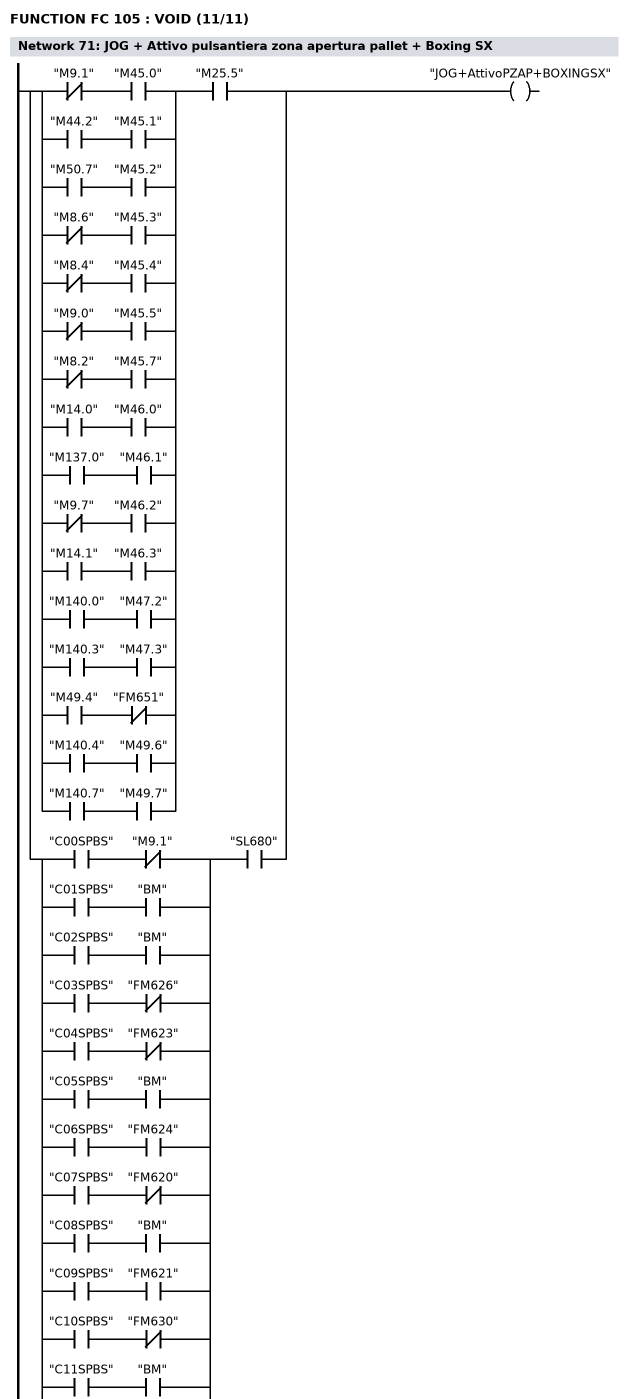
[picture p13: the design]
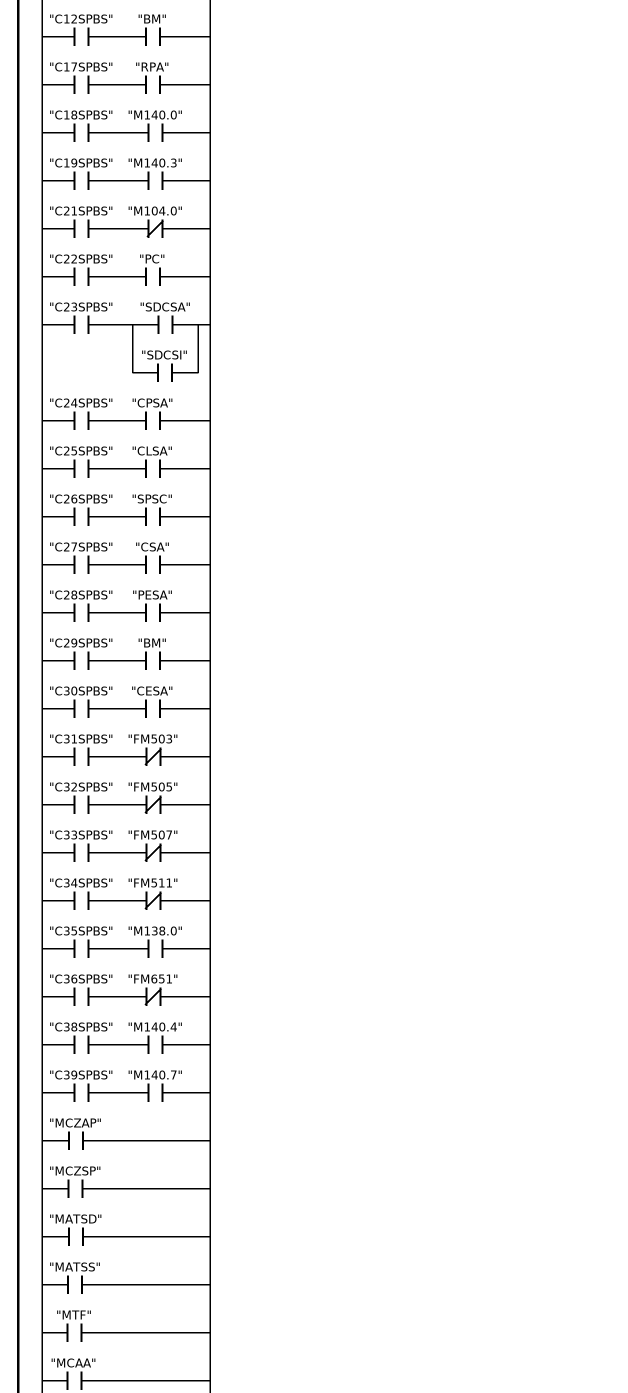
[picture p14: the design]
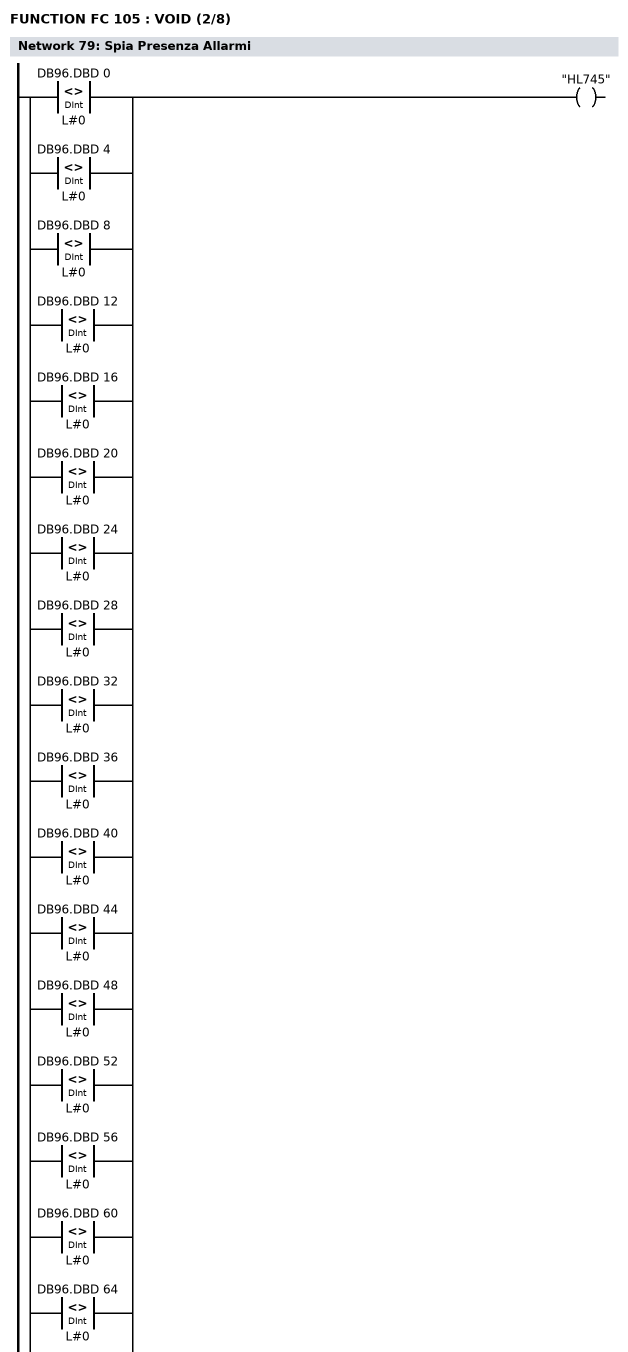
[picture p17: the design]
FUNCTION FC 105 : VOID
TITLE =Gestione Output
AUTHOR : MassimoZ
FAMILY : NovaSrl
VERSION : 0.1

BEGIN
NETWORK
TITLE =Avanti Apertura Pallet

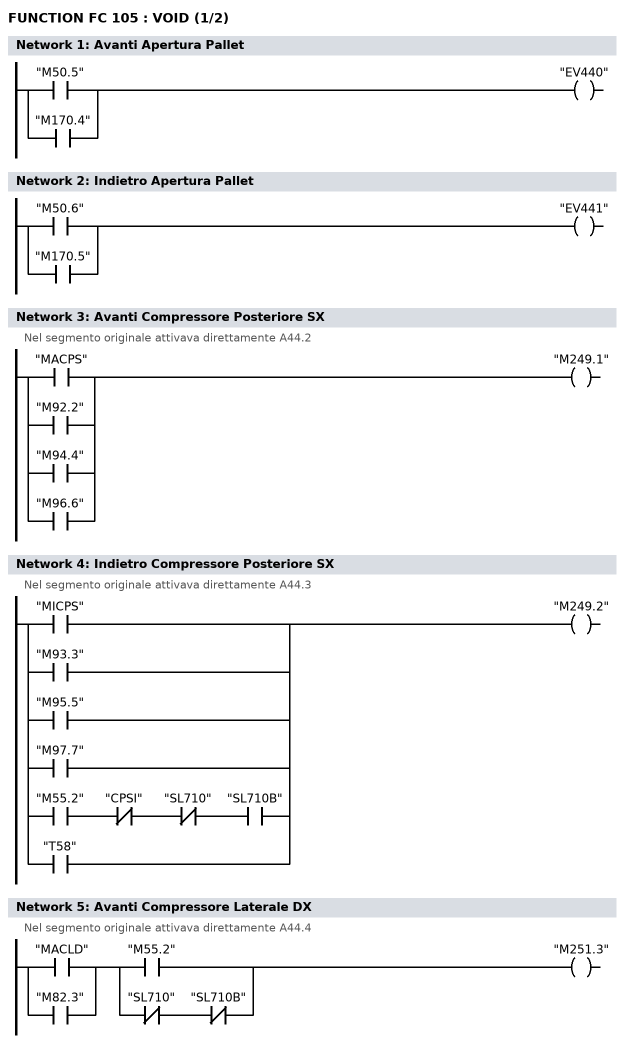
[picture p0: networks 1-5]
      O     "M50.5";
      O     "M170.4";
      =     "EV440";
NETWORK
TITLE =Indietro Apertura Pallet

      O     "M50.6";
      O     "M170.5";
      =     "EV441";
NETWORK
TITLE =Avanti Compressore Posteriore SX
//Nel segmento originale attivava direttamente A44.2
      O     "MACPS";
      O     "M92.2";
      O     "M94.4";
      O     "M96.6";
      =     "M249.1";
NETWORK
TITLE =Indietro Compressore Posteriore SX
//Nel segmento originale attivava direttamente A44.3
      O     "MICPS";
      O     "M93.3";
      O     "M95.5";
      O     "M97.7";
      O     ;
      U     "M55.2";
      UN    "CPSI";
      UN    "SL710";
      U     "SL710B";
      O     "T58";
      =     "M249.2";
NETWORK
TITLE =Avanti Compressore Laterale DX
//Nel segmento originale attivava direttamente A44.4
      U(    ;
      O     "MACLD";
      O     "M82.3";
      )     ;
      U(    ;
      O     "M55.2";
      O     ;
      UN    "SL710";
      UN    "SL710B";
      )     ;
      =     "M251.3";
NETWORK
TITLE =Indietro Compressore Laterale DX
//Nel segmento originale attivava direttamente A44.5
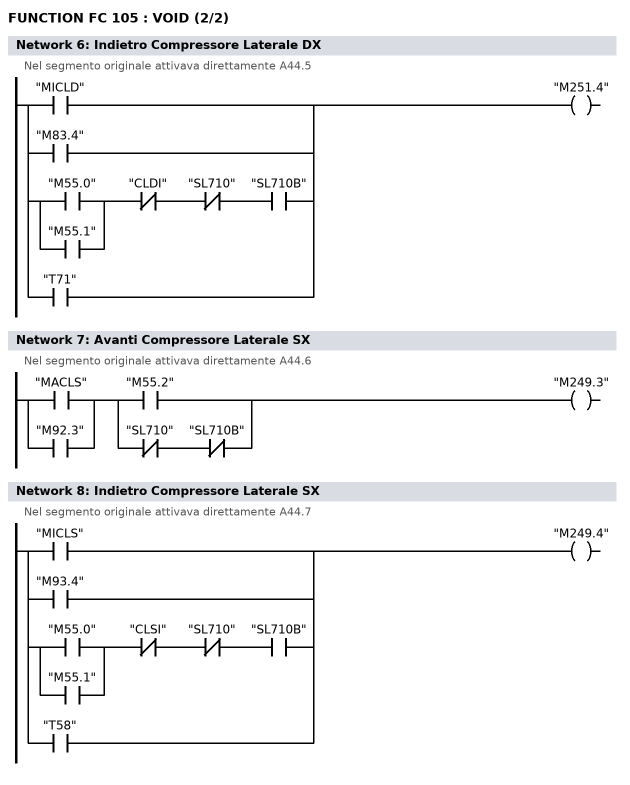
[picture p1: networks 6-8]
      O     "MICLD";
      O     "M83.4";
      O     ;
      U(    ;
      O     "M55.0";
      O     "M55.1";
      )     ;
      UN    "CLDI";
      UN    "SL710";
      U     "SL710B";
      O     "T71";
      =     "M251.4";
NETWORK
TITLE =Avanti Compressore Laterale SX
//Nel segmento originale attivava direttamente A44.6
      U(    ;
      O     "MACLS";
      O     "M92.3";
      )     ;
      U(    ;
      O     "M55.2";
      O     ;
      UN    "SL710";
      UN    "SL710B";
      )     ;
      =     "M249.3";
NETWORK
TITLE =Indietro Compressore Laterale SX
//Nel segmento originale attivava direttamente A44.7
      O     "MICLS";
      O     "M93.4";
      O     ;
      U(    ;
      O     "M55.0";
      O     "M55.1";
      )     ;
      UN    "CLSI";
      UN    "SL710";
      U     "SL710B";
      O     "T58";
      =     "M249.4";
NETWORK
TITLE =Abilita modifica per 12FLB540-CASSA DI COMPRESSIONE SX

      U     "E73.3";
      =     "M249.0";
// Gestione tradizionale con compressore laterale per 1 piantaggio
// e posteriore per 2 e 3 piantaggi
      UN    "M249.0";
      SPBN  M00b;
      U     "M249.1";
      =     "EV442";
      U     "M249.2";
      =     "EV443";
      U     "M249.3";
      =     "EV446";
      U     "M249.4";
      =     "EV447";
M00b: NOP   0;
// Gestione per 12FLB540 con compressore posteriore per 1 piantaggio
// e laterale per 2 e 3 piantaggi
      U     "M249.0";
      SPBN  M00c;
      U     "M249.1";
      =     "EV446";
      U     "M249.2";
      =     "EV447";
      U     "M249.3";
      =     "EV442";
      U     "M249.4";
      =     "EV443";
M00c: NOP   0;

NETWORK
TITLE =Avanti Compressore Posteriore DX
//Nel segmento originale attivava direttamente A45.0
//
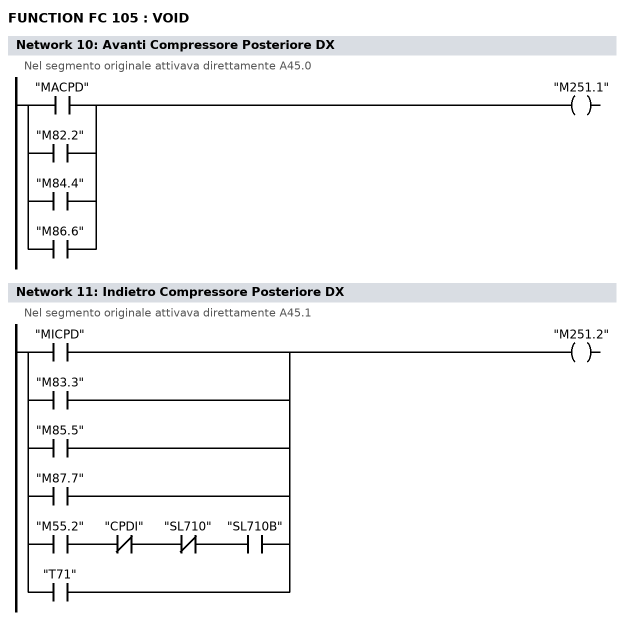
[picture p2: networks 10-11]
      O     "MACPD";
      O     "M82.2";
      O     "M84.4";
      O     "M86.6";
      =     "M251.1";
NETWORK
TITLE =Indietro Compressore Posteriore DX
//Nel segmento originale attivava direttamente A45.1
      O     "MICPD";
      O     "M83.3";
      O     "M85.5";
      O     "M87.7";
      O     ;
      U     "M55.2";
      UN    "CPDI";
      UN    "SL710";
      U     "SL710B";
      O     "T71";
      =     "M251.2";
NETWORK
TITLE =Abilita modifica per 12FLB540-CASSA DI COMPRESSIONE DX

      U     "E73.3";
      =     "M251.0";
// Gestione tradizionale con compressore laterale per 1 piantaggio
// e posteriore per 2 e 3 piantaggi
      UN    "M251.0";
      SPBN  D00b;
      U     "M251.1";
      =     "EV450";
      U     "M251.2";
      =     "EV451";
      U     "M251.3";
      =     "EV444";
      U     "M251.4";
      =     "EV445";
D00b: NOP   0;
// Gestione per 12FLB540 con compressore posteriore per 1 piantaggio
// e laterale per 2 e 3 piantaggi
      U     "M251.0";
      SPBN  D00c;
      U     "M251.1";
      =     "EV444";
      U     "M251.2";
      =     "EV445";
      U     "M251.3";
      =     "EV450";
      U     "M251.4";
      =     "EV451";
D00c: NOP   0;

NETWORK
TITLE =Salita Piantaggio Elementi SX

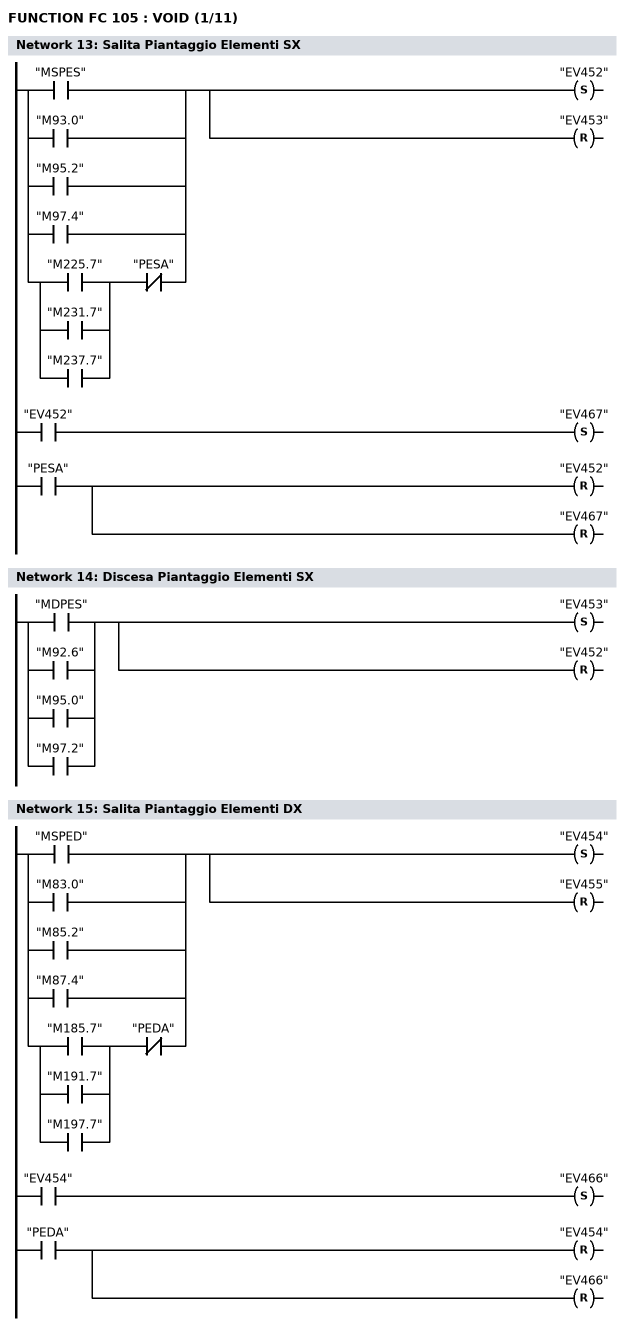
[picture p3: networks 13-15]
      O     "MSPES";
      O     "M93.0";
      O     "M95.2";
      O     "M97.4";
      O(    ;
      O     "M225.7";
      O     "M231.7";
      O     "M237.7";
      UN    "PESA";
      )     ;
      S     "EV452";
      R     "EV453";

      U     "EV452";
      S     "EV467";

      U     "PESA";
      R     "EV452";
      R     "EV467";
NETWORK
TITLE =Discesa Piantaggio Elementi SX

      O     "MDPES";
      O     "M92.6";
      O     "M95.0";
      O     "M97.2";
      S     "EV453";
      R     "EV452";
NETWORK
TITLE =Salita Piantaggio Elementi DX

      O     "MSPED";
      O     "M83.0";
      O     "M85.2";
      O     "M87.4";
      O(    ;
      O     "M185.7";
      O     "M191.7";
      O     "M197.7";
      UN    "PEDA";
      )     ;
      S     "EV454";
      R     "EV455";

      U     "EV454";
      S     "EV466";

      U     "PEDA";
      R     "EV454";
      R     "EV466";
NETWORK
TITLE =Discesa Piantaggio Elementi DX

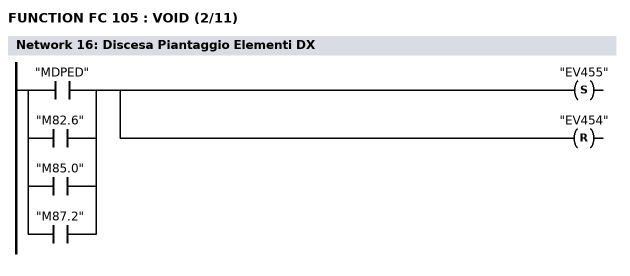
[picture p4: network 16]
      O     "MDPED";
      O     "M82.6";
      O     "M85.0";
      O     "M87.2";
      S     "EV455";
      R     "EV454";
NETWORK
TITLE =EV Pilota Centralina Idraulica

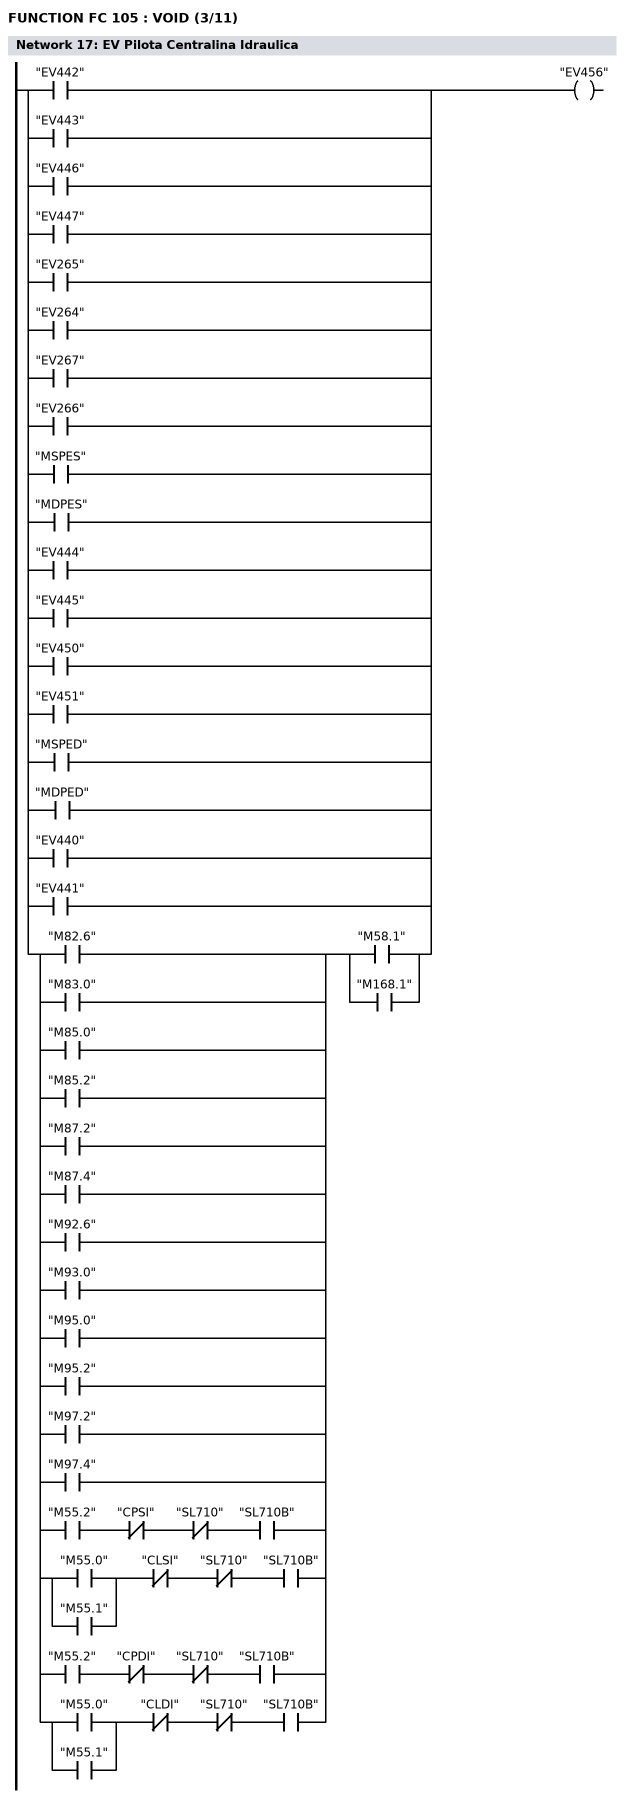
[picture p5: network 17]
      O     "EV442";
      O     "EV443";
      O     "EV446";
      O     "EV447";
      O     "EV265";
      O     "EV264";
      O     "EV267";
      O     "EV266";
      O     "MSPES";
      O     "MDPES";
      O     "EV444";
      O     "EV445";
      O     "EV450";
      O     "EV451";
      O     "MSPED";
      O     "MDPED";
      O     "EV440";
      O     "EV441";
      O     ;
      U(    ;
      O     "M82.6";
      O     "M83.0";
      O     "M85.0";
      O     "M85.2";
      O     "M87.2";
      O     "M87.4";
      O     "M92.6";
      O     "M93.0";
      O     "M95.0";
      O     "M95.2";
      O     "M97.2";
      O     "M97.4";
      O     ;
      U     "M55.2";
      UN    "CPSI";
      UN    "SL710";
      U     "SL710B";
      O     ;
      U(    ;
      O     "M55.0";
      O     "M55.1";
      )     ;
      UN    "CLSI";
      UN    "SL710";
      U     "SL710B";
      O     ;
      U     "M55.2";
      UN    "CPDI";
      UN    "SL710";
      U     "SL710B";
      O     ;
      U(    ;
      O     "M55.0";
      O     "M55.1";
      )     ;
      UN    "CLDI";
      UN    "SL710";
      U     "SL710B";
      )     ;
      U(    ;
      O     "M58.1";
      O     "M168.1";
      )     ;
      =     "EV456";
NETWORK
TITLE =Avanti cadenziatore Entrata SX

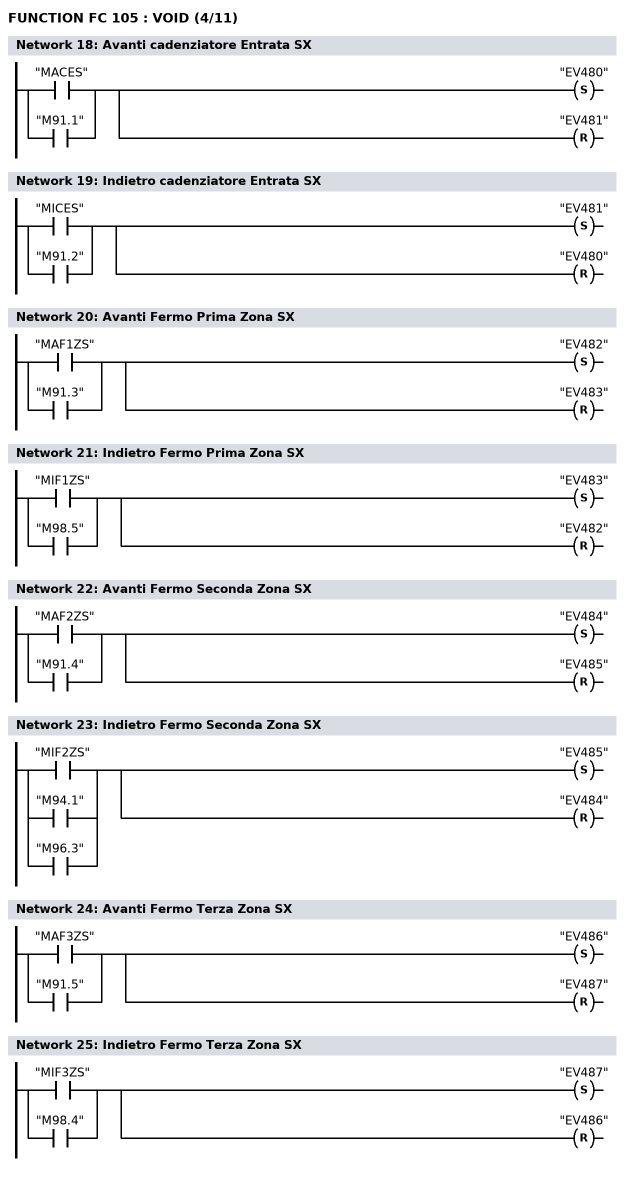
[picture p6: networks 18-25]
      O     "MACES";
      O     "M91.1";
      S     "EV480";
      R     "EV481";
NETWORK
TITLE =Indietro cadenziatore Entrata SX

      O     "MICES";
      O     "M91.2";
      S     "EV481";
      R     "EV480";
NETWORK
TITLE =Avanti Fermo Prima Zona SX

      O     "MAF1ZS";
      O     "M91.3";
      S     "EV482";
      R     "EV483";
NETWORK
TITLE =Indietro Fermo Prima Zona SX

      O     "MIF1ZS";
      O     "M98.5";
      S     "EV483";
      R     "EV482";
NETWORK
TITLE =Avanti Fermo Seconda Zona SX

      O     "MAF2ZS";
      O     "M91.4";
      S     "EV484";
      R     "EV485";
NETWORK
TITLE =Indietro Fermo Seconda Zona SX

      O     "MIF2ZS";
      O     "M94.1";
      O     "M96.3";
      S     "EV485";
      R     "EV484";
NETWORK
TITLE =Avanti Fermo Terza Zona SX

      O     "MAF3ZS";
      O     "M91.5";
      S     "EV486";
      R     "EV487";
NETWORK
TITLE =Indietro Fermo Terza Zona SX

      O     "MIF3ZS";
      O     "M98.4";
      S     "EV487";
      R     "EV486";
NETWORK
TITLE =Avanti Bloccaggio pezzo in Zona di Lavoro SX

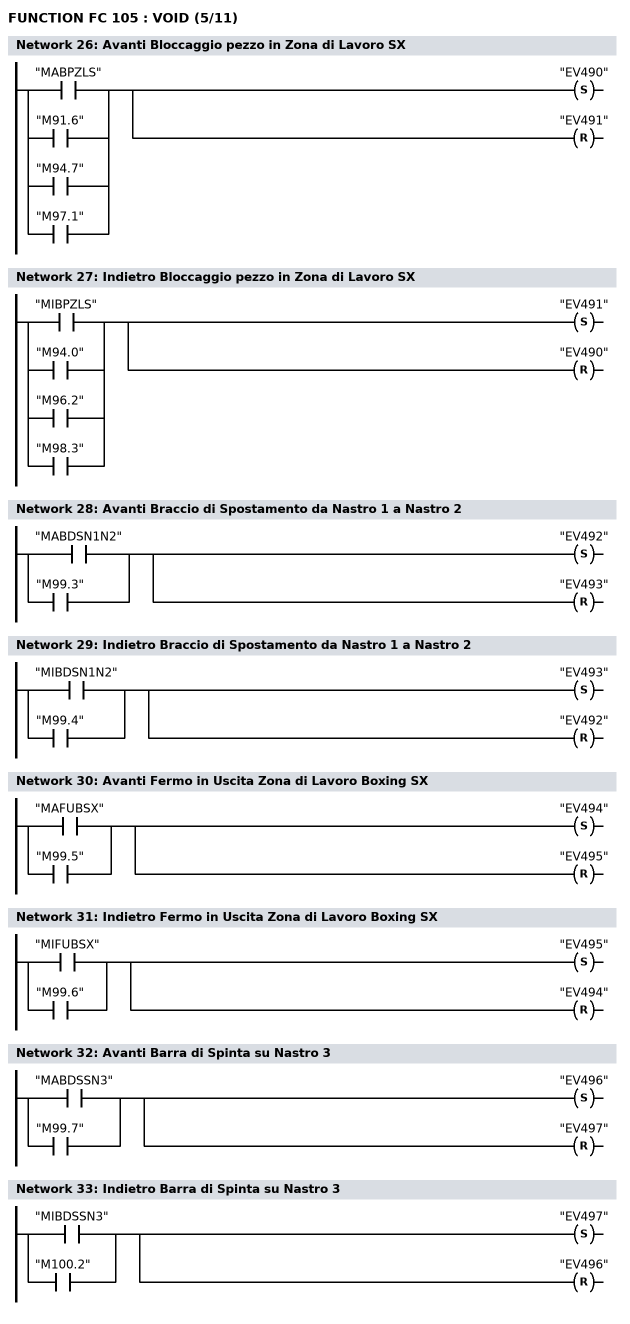
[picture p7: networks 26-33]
      O     "MABPZLS";
      O     "M91.6";
      O     "M94.7";
      O     "M97.1";
      S     "EV490";
      R     "EV491";
NETWORK
TITLE =Indietro Bloccaggio pezzo in Zona di Lavoro SX

      O     "MIBPZLS";
      O     "M94.0";
      O     "M96.2";
      O     "M98.3";
      S     "EV491";
      R     "EV490";
NETWORK
TITLE =Avanti Braccio di Spostamento da Nastro 1 a Nastro 2

      O     "MABDSN1N2";
      O     "M99.3";
      S     "EV492";
      R     "EV493";
NETWORK
TITLE =Indietro Braccio di Spostamento da Nastro 1 a Nastro 2

      O     "MIBDSN1N2";
      O     "M99.4";
      S     "EV493";
      R     "EV492";
NETWORK
TITLE =Avanti Fermo in Uscita Zona di Lavoro Boxing SX

      O     "MAFUBSX";
      O     "M99.5";
      S     "EV494";
      R     "EV495";
NETWORK
TITLE =Indietro Fermo in Uscita Zona di Lavoro Boxing SX

      O     "MIFUBSX";
      O     "M99.6";
      S     "EV495";
      R     "EV494";
NETWORK
TITLE =Avanti Barra di Spinta su Nastro 3

      O     "MABDSSN3";
      O     "M99.7";
      S     "EV496";
      R     "EV497";
NETWORK
TITLE =Indietro Barra di Spinta su Nastro 3

      O     "MIBDSSN3";
      O     "M100.2";
      S     "EV497";
      R     "EV496";
NETWORK
TITLE =Avanti Braccio di Spostamento da Nastro 2 a Nastro 3

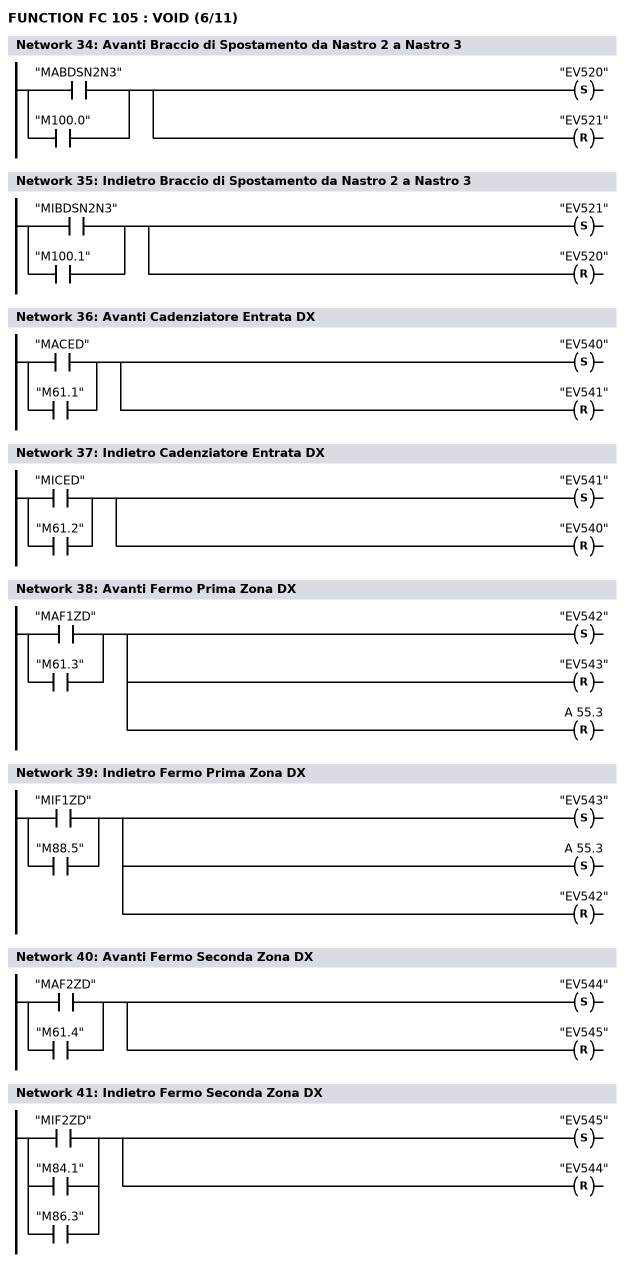
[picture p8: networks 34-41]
      O     "MABDSN2N3";
      O     "M100.0";
      S     "EV520";
      R     "EV521";
NETWORK
TITLE =Indietro Braccio di Spostamento da Nastro 2 a Nastro 3

      O     "MIBDSN2N3";
      O     "M100.1";
      S     "EV521";
      R     "EV520";
NETWORK
TITLE =Avanti Cadenziatore Entrata DX

      O     "MACED";
      O     "M61.1";
      S     "EV540";
      R     "EV541";
NETWORK
TITLE =Indietro Cadenziatore Entrata DX

      O     "MICED";
      O     "M61.2";
      S     "EV541";
      R     "EV540";
NETWORK
TITLE =Avanti Fermo Prima Zona DX

      O     "MAF1ZD";
      O     "M61.3";
      S     "EV542";
      R     "EV543";
      R     A     55.3;
NETWORK
TITLE =Indietro Fermo Prima Zona DX

      O     "MIF1ZD";
      O     "M88.5";
      S     "EV543";
      S     A     55.3;
      R     "EV542";
NETWORK
TITLE =Avanti Fermo Seconda Zona DX

      O     "MAF2ZD";
      O     "M61.4";
      S     "EV544";
      R     "EV545";
NETWORK
TITLE =Indietro Fermo Seconda Zona DX

      O     "MIF2ZD";
      O     "M84.1";
      O     "M86.3";
      S     "EV545";
      R     "EV544";
NETWORK
TITLE =Avanti Fermo Terza Zona DX

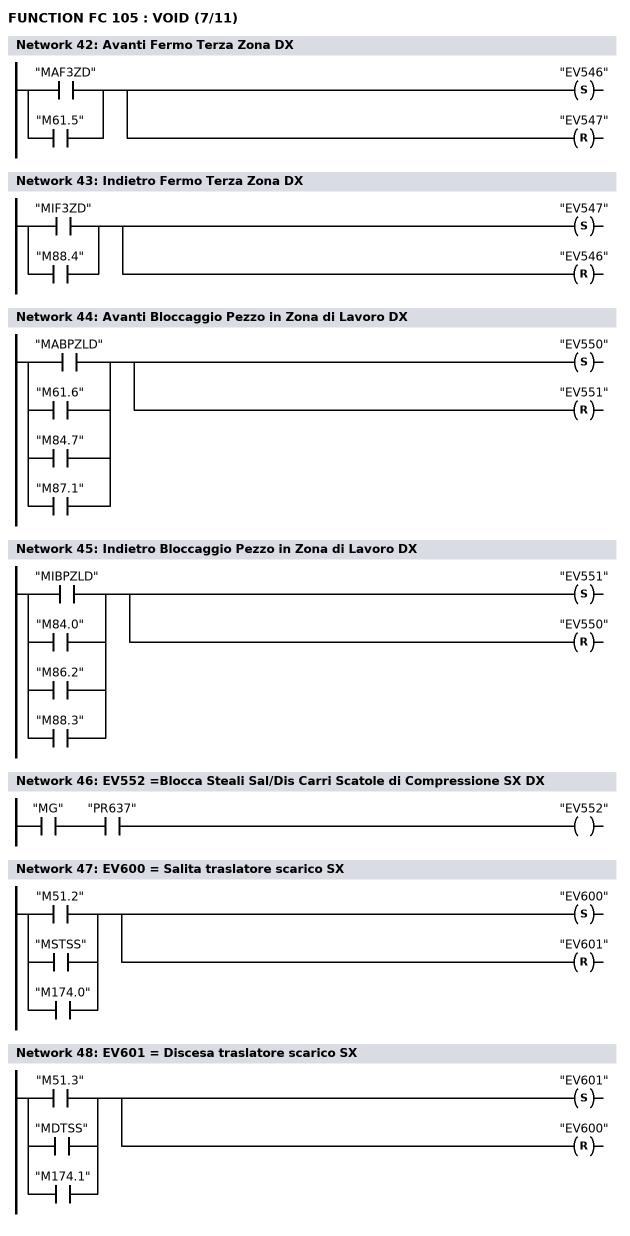
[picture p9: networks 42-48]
      O     "MAF3ZD";
      O     "M61.5";
      S     "EV546";
      R     "EV547";
NETWORK
TITLE =Indietro Fermo Terza Zona DX

      O     "MIF3ZD";
      O     "M88.4";
      S     "EV547";
      R     "EV546";
NETWORK
TITLE =Avanti Bloccaggio Pezzo in Zona di Lavoro DX

      O     "MABPZLD";
      O     "M61.6";
      O     "M84.7";
      O     "M87.1";
      S     "EV550";
      R     "EV551";
NETWORK
TITLE =Indietro Bloccaggio Pezzo in Zona di Lavoro DX

      O     "MIBPZLD";
      O     "M84.0";
      O     "M86.2";
      O     "M88.3";
      S     "EV551";
      R     "EV550";
NETWORK
TITLE =EV552 =Blocca Steali Sal/Dis Carri Scatole di Compressione SX DX

      U     "MG";
      U     "PR637";
      =     "EV552";
NETWORK
TITLE =EV600 = Salita traslatore scarico SX

      O     "M51.2";
      O     "MSTSS";
      O     "M174.0";
      S     "EV600";
      R     "EV601";
NETWORK
TITLE =EV601 = Discesa traslatore scarico SX

      O     "M51.3";
      O     "MDTSS";
      O     "M174.1";
      S     "EV601";
      R     "EV600";
NETWORK
TITLE =EV602 = Salita traslatore scarico DX

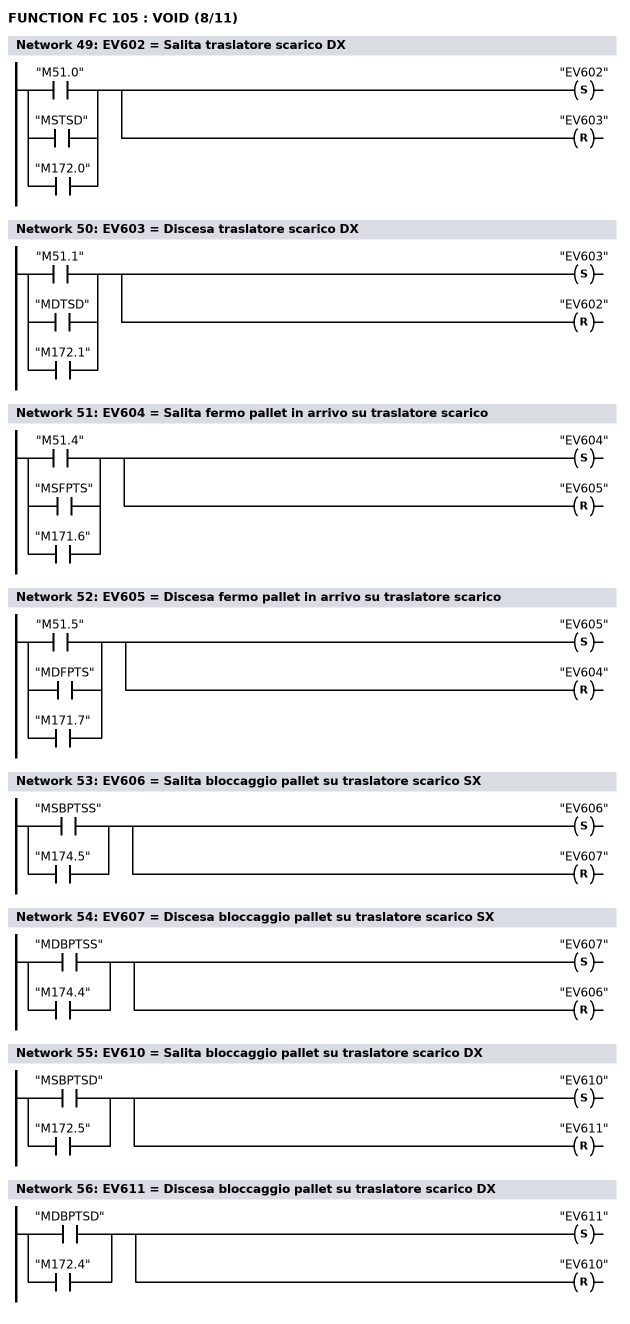
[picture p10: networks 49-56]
      O     "M51.0";
      O     "MSTSD";
      O     "M172.0";
      S     "EV602";
      R     "EV603";
NETWORK
TITLE =EV603 = Discesa traslatore scarico DX

      O     "M51.1";
      O     "MDTSD";
      O     "M172.1";
      S     "EV603";
      R     "EV602";
NETWORK
TITLE =EV604 = Salita fermo pallet in arrivo su traslatore scarico

      O     "M51.4";
      O     "MSFPTS";
      O     "M171.6";
      S     "EV604";
      R     "EV605";
NETWORK
TITLE =EV605 = Discesa fermo pallet in arrivo su traslatore scarico

      O     "M51.5";
      O     "MDFPTS";
      O     "M171.7";
      S     "EV605";
      R     "EV604";
NETWORK
TITLE =EV606 = Salita bloccaggio pallet su traslatore scarico SX

      O     "MSBPTSS";
      O     "M174.5";
      S     "EV606";
      R     "EV607";
NETWORK
TITLE =EV607 = Discesa bloccaggio pallet su traslatore scarico SX

      O     "MDBPTSS";
      O     "M174.4";
      S     "EV607";
      R     "EV606";
NETWORK
TITLE =EV610 = Salita bloccaggio pallet su traslatore scarico DX

      O     "MSBPTSD";
      O     "M172.5";
      S     "EV610";
      R     "EV611";
NETWORK
TITLE =EV611 = Discesa bloccaggio pallet su traslatore scarico DX

      O     "MDBPTSD";
      O     "M172.4";
      S     "EV611";
      R     "EV610";
NETWORK
TITLE =EV612 = Salita traslatore finale

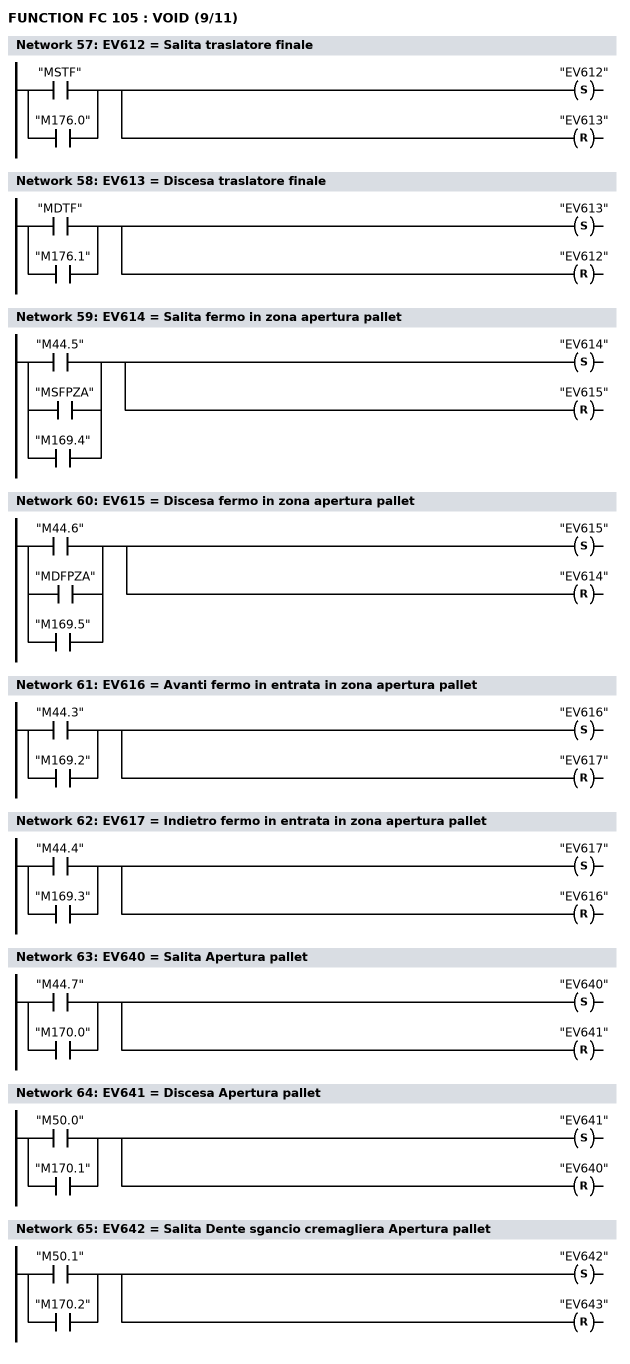
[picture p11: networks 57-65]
      O     "MSTF";
      O     "M176.0";
      S     "EV612";
      R     "EV613";
NETWORK
TITLE =EV613 = Discesa traslatore finale

      O     "MDTF";
      O     "M176.1";
      S     "EV613";
      R     "EV612";
NETWORK
TITLE =EV614 = Salita fermo in zona apertura pallet

      O     "M44.5";
      O     "MSFPZA";
      O     "M169.4";
      S     "EV614";
      R     "EV615";
NETWORK
TITLE =EV615 = Discesa fermo in zona apertura pallet

      O     "M44.6";
      O     "MDFPZA";
      O     "M169.5";
      S     "EV615";
      R     "EV614";
NETWORK
TITLE =EV616 = Avanti fermo in entrata in zona apertura pallet

      O     "M44.3";
      O     "M169.2";
      S     "EV616";
      R     "EV617";
NETWORK
TITLE =EV617 = Indietro fermo in entrata in zona apertura pallet

      O     "M44.4";
      O     "M169.3";
      S     "EV617";
      R     "EV616";
NETWORK
TITLE =EV640 = Salita Apertura pallet

      O     "M44.7";
      O     "M170.0";
      S     "EV640";
      R     "EV641";
NETWORK
TITLE =EV641 = Discesa Apertura pallet

      O     "M50.0";
      O     "M170.1";
      S     "EV641";
      R     "EV640";
NETWORK
TITLE =EV642 = Salita Dente sgancio cremagliera Apertura pallet

      O     "M50.1";
      O     "M170.2";
      S     "EV642";
      R     "EV643";
NETWORK
TITLE =EV643 = Discesa Dente sgancio cremagliera Apertura pallet

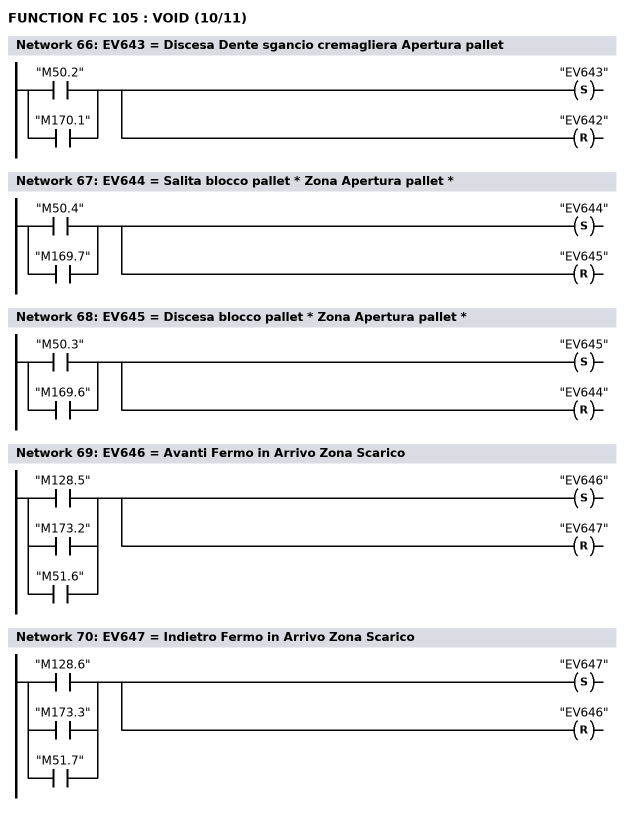
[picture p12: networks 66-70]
      O     "M50.2";
      O     "M170.1";
      S     "EV643";
      R     "EV642";
NETWORK
TITLE =EV644 = Salita blocco pallet * Zona Apertura pallet *

      O     "M50.4";
      O     "M169.7";
      S     "EV644";
      R     "EV645";
NETWORK
TITLE =EV645 = Discesa blocco pallet * Zona Apertura pallet *

      O     "M50.3";
      O     "M169.6";
      S     "EV645";
      R     "EV644";
NETWORK
TITLE =EV646 = Avanti Fermo in Arrivo Zona Scarico

      O     "M128.5";
      O     "M173.2";
      O     "M51.6";
      S     "EV646";
      R     "EV647";
NETWORK
TITLE =EV647 = Indietro Fermo in Arrivo Zona Scarico

      O     "M128.6";
      O     "M173.3";
      O     "M51.7";
      S     "EV647";
      R     "EV646";
NETWORK
TITLE =JOG + Attivo pulsantiera zona apertura pallet + Boxing SX

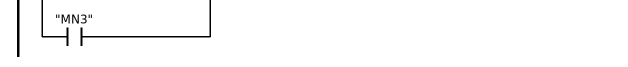
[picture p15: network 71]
      O(    ;
      U(    ;
      UN    "M9.1";
      U     "M45.0";
      O     ;
      U     "M44.2";
      U     "M45.1";
      O     ;
      U     "M50.7";
      U     "M45.2";
      O     ;
      UN    "M8.6";
      U     "M45.3";
      O     ;
      UN    "M8.4";
      U     "M45.4";
      O     ;
      UN    "M9.0";
      U     "M45.5";
      O     ;
      UN    "M8.2";
      U     "M45.7";
      O     ;
      U     "M14.0";
      U     "M46.0";
      O     ;
      U     "M137.0";
      U     "M46.1";
      O     ;
      UN    "M9.7";
      U     "M46.2";
      O     ;
      U     "M14.1";
      U     "M46.3";
      O     ;
      U     "M140.0";
      U     "M47.2";
      O     ;
      U     "M140.3";
      U     "M47.3";
      O     ;
      U     "M49.4";
      UN    "FM651";
      O     ;
      U     "M140.4";
      U     "M49.6";
      O     ;
      U     "M140.7";
      U     "M49.7";
      )     ;
      U     "M25.5";
      )     ;
      O(    ;
      U(    ;
      U     "C00SPBS";
      UN    "M9.1";
      O     ;
      U     "C01SPBS";
      U     "BM";
      O     ;
      U     "C02SPBS";
      U     "BM";
      O     ;
      U     "C03SPBS";
      UN    "FM626";
      O     ;
      U     "C04SPBS";
      UN    "FM623";
      O     ;
      U     "C05SPBS";
      U     "BM";
      O     ;
      U     "C06SPBS";
      U     "FM624";
      O     ;
      U     "C07SPBS";
      UN    "FM620";
      O     ;
      U     "C08SPBS";
      U     "BM";
      O     ;
      U     "C09SPBS";
      U     "FM621";
      O     ;
      U     "C10SPBS";
      UN    "FM630";
      O     ;
      U     "C11SPBS";
      U     "BM";
      O     ;
      U     "C12SPBS";
      U     "BM";
      O     ;
      U     "C17SPBS";
      U     "RPA";
      O     ;
      U     "C18SPBS";
      U     "M140.0";
      O     ;
      U     "C19SPBS";
      U     "M140.3";
      O     ;
      U     "C21SPBS";
      UN    "M104.0";
      O     ;
      U     "C22SPBS";
      U     "PC";
      O     ;
      U     "C23SPBS";
      U(    ;
      O     "SDCSA";
      O     "SDCSI";
      )     ;
      O     ;
      U     "C24SPBS";
      U     "CPSA";
      O     ;
      U     "C25SPBS";
      U     "CLSA";
      O     ;
      U     "C26SPBS";
      U     "SPSC";
      O     ;
      U     "C27SPBS";
      U     "CSA";
      O     ;
      U     "C28SPBS";
      U     "PESA";
      O     ;
      U     "C29SPBS";
      U     "BM";
      O     ;
      U     "C30SPBS";
      U     "CESA";
      O     ;
      U     "C31SPBS";
      UN    "FM503";
      O     ;
      U     "C32SPBS";
      UN    "FM505";
      O     ;
      U     "C33SPBS";
      UN    "FM507";
      O     ;
      U     "C34SPBS";
      UN    "FM511";
      O     ;
      U     "C35SPBS";
      U     "M138.0";
      O     ;
      U     "C36SPBS";
      UN    "FM651";
      O     ;
      U     "C38SPBS";
      U     "M140.4";
      O     ;
      U     "C39SPBS";
      U     "M140.7";
      O     ;
      O     "MCZAP";
      O     "MCZSP";
      O     "MATSD";
      O     "MATSS";
      O     "MTF";
      O     "MCAA";
      O     "MN3";
      )     ;
      U     "SL680";
      )     ;
      =     "JOG+AttivoPZAP+BOXINGSX";
NETWORK
TITLE =JOG - Attivo pulsantiera zona apertura pallet + Boxing SX

      O(    ;
      U(    ;
      U     "M9.1";
      U     "M45.0";
      O     ;
      U     "M8.6";
      U     "M45.3";
      O     ;
      U     "M8.4";
      U     "M45.4";
      O     ;
      U     "M9.0";
      U     "M45.5";
      O     ;
      U     "M8.2";
      U     "M45.7";
      O     ;
      UN    "M14.0";
      U     "M46.0";
      O     ;
      U     "M9.6";
      U     "M46.1";
      O     ;
      U     "M9.7";
      U     "M46.2";
      O     ;
      U     "M13.7";
      U     "M46.3";
      O     ;
      U     "M140.1";
      U     "M47.2";
      O     ;
      U     "M140.2";
      U     "M47.3";
      O     ;
      U     "M49.4";
      U     "FM651";
      O     ;
      U     "M140.5";
      U     "M49.6";
      O     ;
      U     "M140.6";
      U     "M49.7";
      )     ;
      U     "M25.5";
      )     ;
      O(    ;
      U(    ;
      U     "C00SPBS";
      U     "M9.1";
      O     ;
      U     "C01SPBS";
      U     "BM";
      O     ;
      U     "C02SPBS";
      U     "BM";
      O     ;
      U     "C03SPBS";
      U     "FM626";
      O     ;
      U     "C04SPBS";
      U     "FM623";
      O     ;
      U     "C05SPBS";
      U     "BM";
      O     ;
      U     "C06SPBS";
      UN    "FM624";
      O     ;
      U     "C07SPBS";
      U     "FM620";
      O     ;
      U     "C08SPBS";
      U     "BM";
      O     ;
      U     "C09SPBS";
      UN    "FM621";
      O     ;
      U     "C10SPBS";
      U     "FM630";
      O     ;
      U     "C11SPBS";
      U     "BM";
      O     ;
      U     "C12SPBS";
      U     "BM";
      O     ;
      U     "C17SPBS";
      U     "M103.7";
      O     ;
      U     "C18SPBS";
      U     "M140.1";
      O     ;
      U     "C19SPBS";
      U     "M140.2";
      O     ;
      U     "C21SPBS";
      U     "M104.0";
      O     ;
      U     "C22SPBS";
      U     "PA";
      O     ;
      U     "C23SPBS";
      U(    ;
      O     "SDCSB";
      O     "SDCSI";
      )     ;
      O     ;
      U     "C24SPBS";
      U     "CPSI";
      O     ;
      U     "C25SPBS";
      U     "CLSI";
      O     ;
      U     "C26SPBS";
      U     "SPSA";
      O     ;
      U     "C27SPBS";
      U     "CSI";
      O     ;
      U     "C28SPBS";
      U     "PESB";
      O     ;
      U     "C29SPBS";
      U     "BM";
      O     ;
      U     "C30SPBS";
      U     "CESI";
      O     ;
      U     "C31SPBS";
      U     "FM503";
      O     ;
      U     "C32SPBS";
      U     "FM505";
      O     ;
      U     "C33SPBS";
      U     "FM507";
      O     ;
      U     "C34SPBS";
      U     "FM511";
      O     ;
      U     "C35SPBS";
      U     "M138.1";
      O     ;
      U     "C36SPBS";
      U     "FM651";
      O     ;
      O     ;
      U     "C38SPBS";
      U     "M140.5";
      O     ;
      U     "C39SPBS";
      U     "M140.6";
      O     ;
      O     "MITSD";
      O     "MITSS";
      )     ;
      U     "SL680";
      )     ;
      =     "JOG-AttivoPZAP+BOXINGSX";
NETWORK
TITLE =HL684 = Spia Zona Boxing In Ciclo

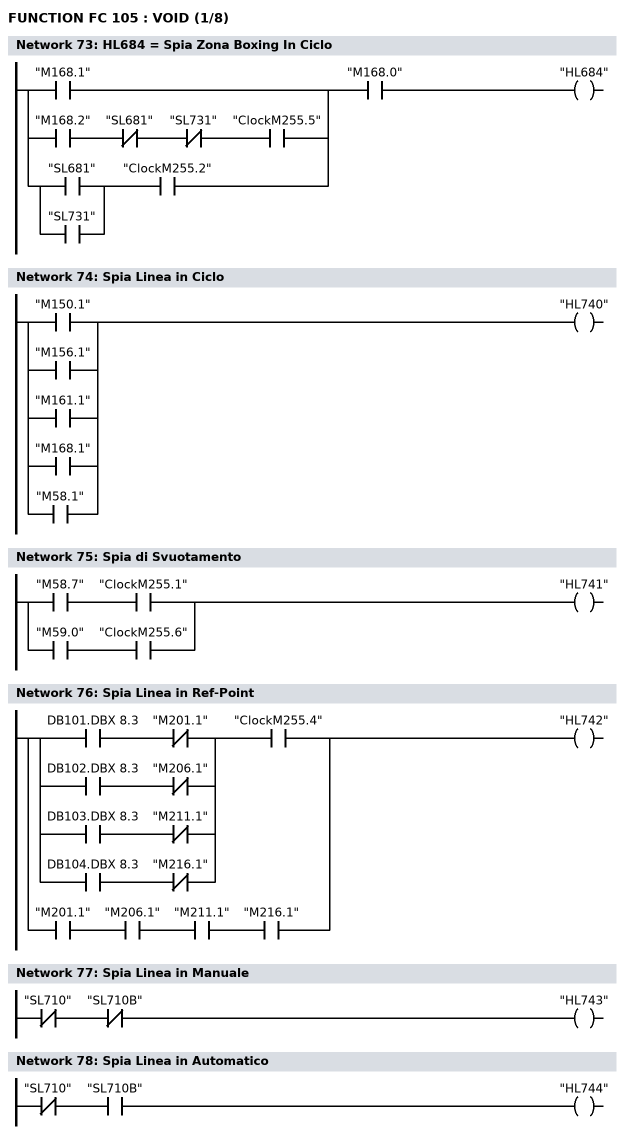
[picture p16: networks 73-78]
      U(    ;
      O     "M168.1";
      O     ;
      U     "M168.2";
      UN    "SL681";
      UN    "SL731";
      U     "ClockM255.5";
      O     ;
      U(    ;
      O     "SL681";
      O     "SL731";
      )     ;
      U     "ClockM255.2";
      )     ;
      U     "M168.0";
      =     "HL684";
NETWORK
TITLE =Spia Linea in Ciclo

      O     "M150.1";
      O     "M156.1";
      O     "M161.1";
      O     "M168.1";
      O     "M58.1";
      =     "HL740";
NETWORK
TITLE =Spia di Svuotamento

      U     "M58.7";
      U     "ClockM255.1";
      O     ;
      U     "M59.0";
      U     "ClockM255.6";
      =     "HL741";
NETWORK
TITLE =Spia Linea in Ref-Point

      U(    ;
      U     DB101.DBX    8.3;
      UN    "M201.1";
      O     ;
      U     DB102.DBX    8.3;
      UN    "M206.1";
      O     ;
      U     DB103.DBX    8.3;
      UN    "M211.1";
      O     ;
      U     DB104.DBX    8.3;
      UN    "M216.1";
      )     ;
      U     "ClockM255.4";
      O     ;
      U     "M201.1";
      U     "M206.1";
      U     "M211.1";
      U     "M216.1";
      =     "HL742";
NETWORK
TITLE =Spia Linea in Manuale

      UN    "SL710";
      UN    "SL710B";
      =     "HL743";
NETWORK
TITLE =Spia Linea in Automatico

      UN    "SL710";
      U     "SL710B";
      =     "HL744";
NETWORK
TITLE =Spia Presenza Allarmi

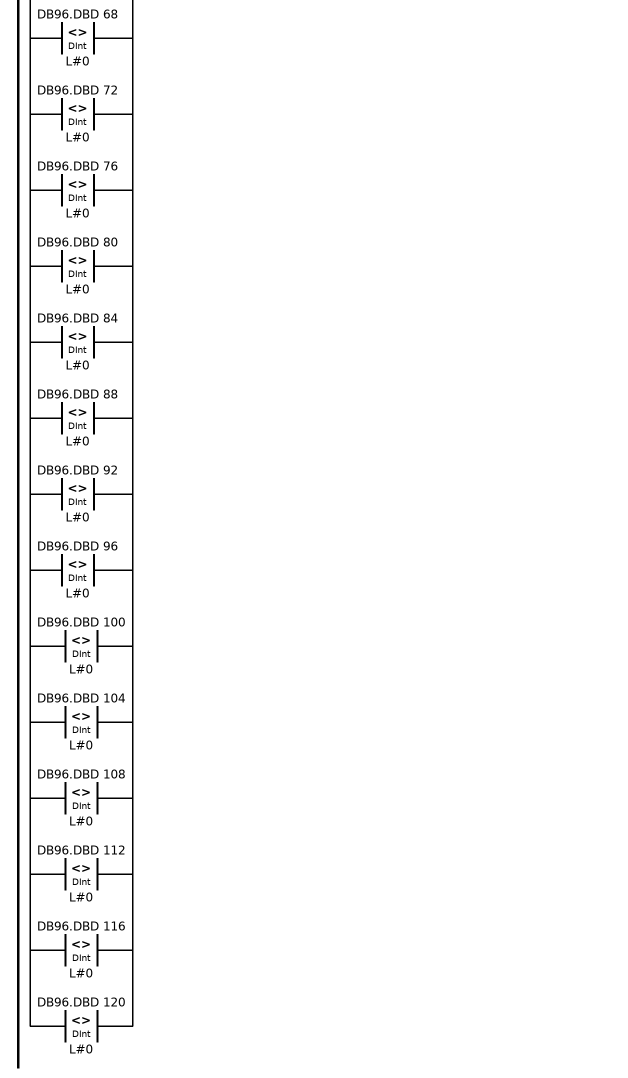
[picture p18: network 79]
      O(    ;
      L     DB96.DBD    0;
      L     L#0;
      <>D   ;
      )     ;
      O(    ;
      L     DB96.DBD    4;
      L     L#0;
      <>D   ;
      )     ;
      O(    ;
      L     DB96.DBD    8;
      L     L#0;
      <>D   ;
      )     ;
      O(    ;
      L     DB96.DBD   12;
      L     L#0;
      <>D   ;
      )     ;
      O(    ;
      L     DB96.DBD   16;
      L     L#0;
      <>D   ;
      )     ;
      O(    ;
      L     DB96.DBD   20;
      L     L#0;
      <>D   ;
      )     ;
      O(    ;
      L     DB96.DBD   24;
      L     L#0;
      <>D   ;
      )     ;
      O(    ;
      L     DB96.DBD   28;
      L     L#0;
      <>D   ;
      )     ;
      O(    ;
      L     DB96.DBD   32;
      L     L#0;
      <>D   ;
      )     ;
      O(    ;
      L     DB96.DBD   36;
      L     L#0;
      <>D   ;
      )     ;
      O(    ;
      L     DB96.DBD   40;
      L     L#0;
      <>D   ;
      )     ;
      O(    ;
      L     DB96.DBD   44;
      L     L#0;
      <>D   ;
      )     ;
      O(    ;
      L     DB96.DBD   48;
      L     L#0;
      <>D   ;
      )     ;
      O(    ;
      L     DB96.DBD   52;
      L     L#0;
      <>D   ;
      )     ;
      O(    ;
      L     DB96.DBD   56;
      L     L#0;
      <>D   ;
      )     ;
      O(    ;
      L     DB96.DBD   60;
      L     L#0;
      <>D   ;
      )     ;
      O(    ;
      L     DB96.DBD   64;
      L     L#0;
      <>D   ;
      )     ;
      O(    ;
      L     DB96.DBD   68;
      L     L#0;
      <>D   ;
      )     ;
      O(    ;
      L     DB96.DBD   72;
      L     L#0;
      <>D   ;
      )     ;
      O(    ;
      L     DB96.DBD   76;
      L     L#0;
      <>D   ;
      )     ;
      O(    ;
      L     DB96.DBD   80;
      L     L#0;
      <>D   ;
      )     ;
      O(    ;
      L     DB96.DBD   84;
      L     L#0;
      <>D   ;
      )     ;
      O(    ;
      L     DB96.DBD   88;
      L     L#0;
      <>D   ;
      )     ;
      O(    ;
      L     DB96.DBD   92;
      L     L#0;
      <>D   ;
      )     ;
      O(    ;
      L     DB96.DBD   96;
      L     L#0;
      <>D   ;
      )     ;
      O(    ;
      L     DB96.DBD  100;
      L     L#0;
      <>D   ;
      )     ;
      O(    ;
      L     DB96.DBD  104;
      L     L#0;
      <>D   ;
      )     ;
      O(    ;
      L     DB96.DBD  108;
      L     L#0;
      <>D   ;
      )     ;
      O(    ;
      L     DB96.DBD  112;
      L     L#0;
      <>D   ;
      )     ;
      O(    ;
      L     DB96.DBD  116;
      L     L#0;
      <>D   ;
      )     ;
      O(    ;
      L     DB96.DBD  120;
      L     L#0;
      <>D   ;
      )     ;
      =     "HL745";
NETWORK
TITLE =Spia Linea in Emergenza

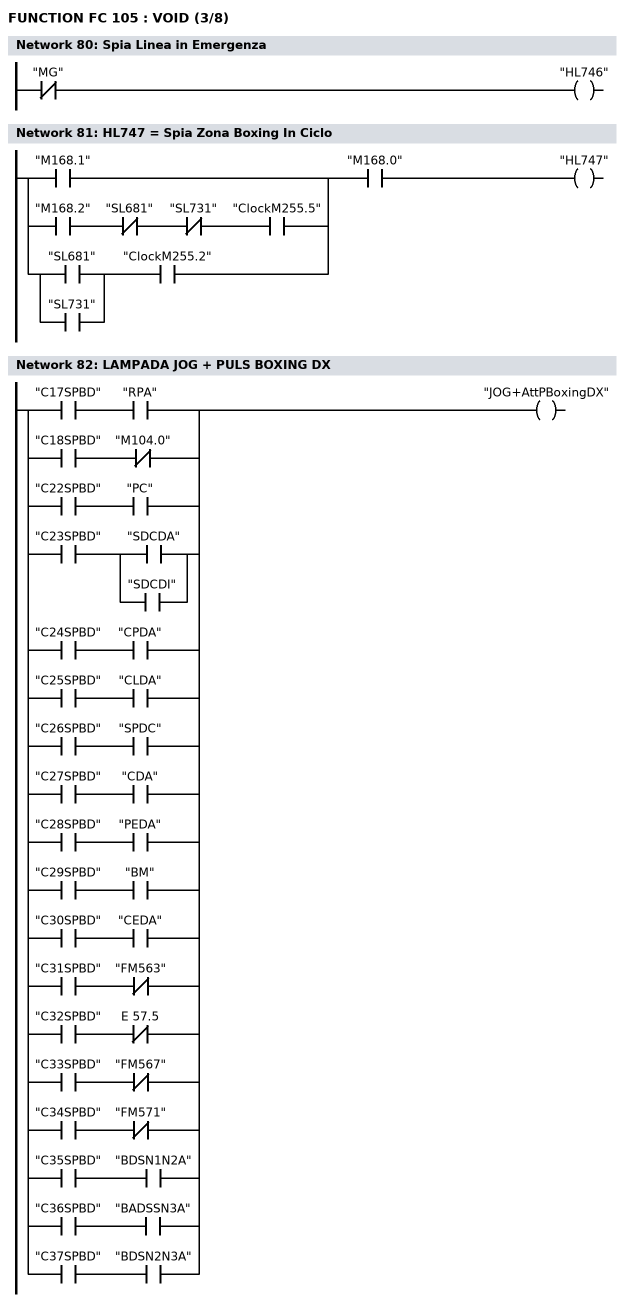
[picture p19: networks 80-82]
      UN    "MG";
      =     "HL746";
NETWORK
TITLE =HL747 = Spia Zona Boxing In Ciclo

      U(    ;
      O     "M168.1";
      O     ;
      U     "M168.2";
      UN    "SL681";
      UN    "SL731";
      U     "ClockM255.5";
      O     ;
      U(    ;
      O     "SL681";
      O     "SL731";
      )     ;
      U     "ClockM255.2";
      )     ;
      U     "M168.0";
      =     "HL747";
NETWORK
TITLE =LAMPADA JOG + PULS BOXING DX

      U     "C17SPBD";
      U     "RPA";
      O     ;
      U     "C18SPBD";
      UN    "M104.0";
      O     ;
      U     "C22SPBD";
      U     "PC";
      O     ;
      U     "C23SPBD";
      U(    ;
      O     "SDCDA";
      O     "SDCDI";
      )     ;
      O     ;
      U     "C24SPBD";
      U     "CPDA";
      O     ;
      U     "C25SPBD";
      U     "CLDA";
      O     ;
      U     "C26SPBD";
      U     "SPDC";
      O     ;
      U     "C27SPBD";
      U     "CDA";
      O     ;
      U     "C28SPBD";
      U     "PEDA";
      O     ;
      U     "C29SPBD";
      U     "BM";
      O     ;
      U     "C30SPBD";
      U     "CEDA";
      O     ;
      U     "C31SPBD";
      UN    "FM563";
      O     ;
      U     "C32SPBD";
      UN    E     57.5;
      O     ;
      U     "C33SPBD";
      UN    "FM567";
      O     ;
      U     "C34SPBD";
      UN    "FM571";
      O     ;
      U     "C35SPBD";
      U     "BDSN1N2A";
      O     ;
      U     "C36SPBD";
      U     "BADSSN3A";
      O     ;
      U     "C37SPBD";
      U     "BDSN2N3A";
      =     "JOG+AttPBoxingDX";
NETWORK
TITLE =LAMPADA JOG - PULS BOXING DX

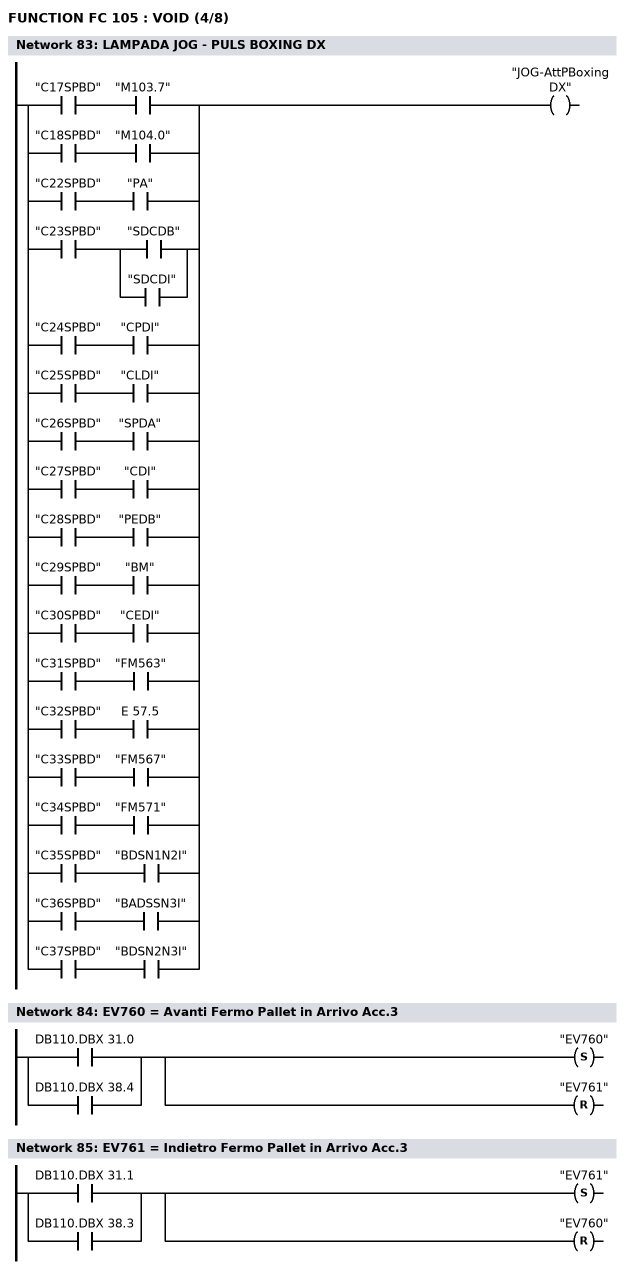
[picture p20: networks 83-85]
      U     "C17SPBD";
      U     "M103.7";
      O     ;
      U     "C18SPBD";
      U     "M104.0";
      O     ;
      U     "C22SPBD";
      U     "PA";
      O     ;
      U     "C23SPBD";
      U(    ;
      O     "SDCDB";
      O     "SDCDI";
      )     ;
      O     ;
      U     "C24SPBD";
      U     "CPDI";
      O     ;
      U     "C25SPBD";
      U     "CLDI";
      O     ;
      U     "C26SPBD";
      U     "SPDA";
      O     ;
      U     "C27SPBD";
      U     "CDI";
      O     ;
      U     "C28SPBD";
      U     "PEDB";
      O     ;
      U     "C29SPBD";
      U     "BM";
      O     ;
      U     "C30SPBD";
      U     "CEDI";
      O     ;
      U     "C31SPBD";
      U     "FM563";
      O     ;
      U     "C32SPBD";
      U     E     57.5;
      O     ;
      U     "C33SPBD";
      U     "FM567";
      O     ;
      U     "C34SPBD";
      U     "FM571";
      O     ;
      U     "C35SPBD";
      U     "BDSN1N2I";
      O     ;
      U     "C36SPBD";
      U     "BADSSN3I";
      O     ;
      U     "C37SPBD";
      U     "BDSN2N3I";
      =     "JOG-AttPBoxingDX";
NETWORK
TITLE =EV760 = Avanti Fermo Pallet in Arrivo Acc.3

      O     DB110.DBX   31.0;
      O     DB110.DBX   38.4;
      S     "EV760";
      R     "EV761";
NETWORK
TITLE =EV761 = Indietro Fermo Pallet in Arrivo Acc.3

      O     DB110.DBX   31.1;
      O     DB110.DBX   38.3;
      S     "EV761";
      R     "EV760";
NETWORK
TITLE =EV762 = Salita Traslatore Posizione di Carico 1 Acc.3

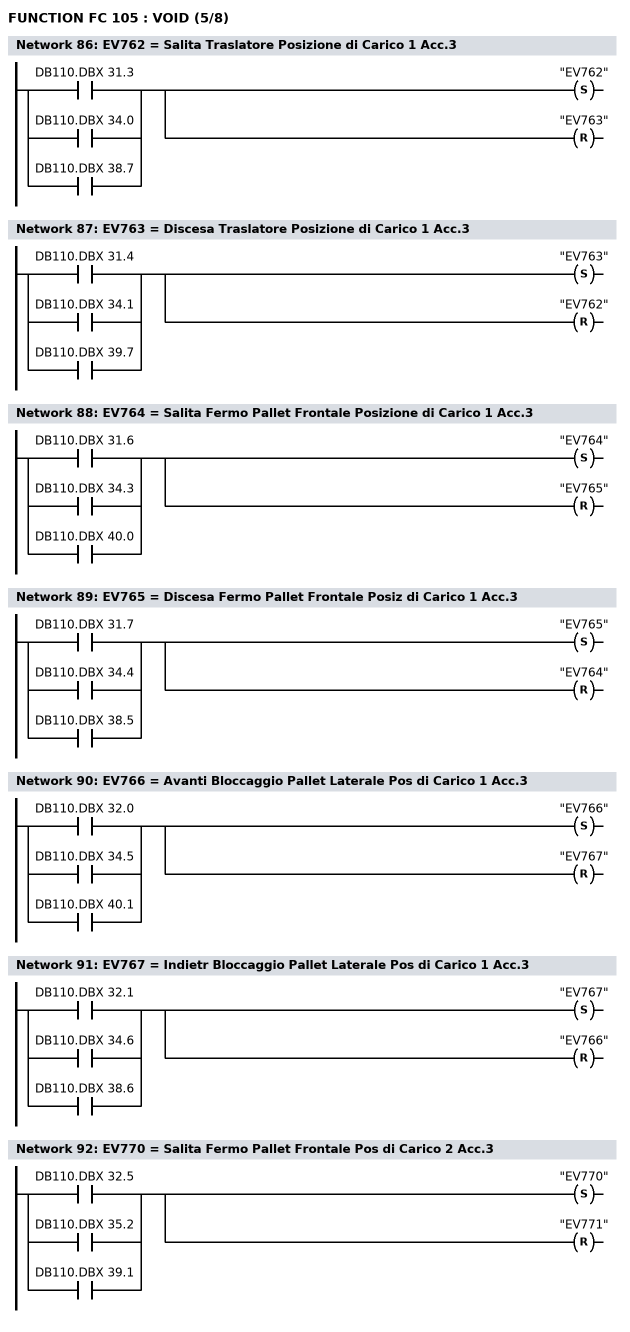
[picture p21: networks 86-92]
      O     DB110.DBX   31.3;
      O     DB110.DBX   34.0;
      O     DB110.DBX   38.7;
      S     "EV762";
      R     "EV763";
NETWORK
TITLE =EV763 = Discesa Traslatore Posizione di Carico 1 Acc.3

      O     DB110.DBX   31.4;
      O     DB110.DBX   34.1;
      O     DB110.DBX   39.7;
      S     "EV763";
      R     "EV762";
NETWORK
TITLE =EV764 = Salita Fermo Pallet Frontale Posizione di Carico 1 Acc.3

      O     DB110.DBX   31.6;
      O     DB110.DBX   34.3;
      O     DB110.DBX   40.0;
      S     "EV764";
      R     "EV765";
NETWORK
TITLE =EV765 = Discesa Fermo Pallet Frontale Posiz di Carico 1 Acc.3

      O     DB110.DBX   31.7;
      O     DB110.DBX   34.4;
      O     DB110.DBX   38.5;
      S     "EV765";
      R     "EV764";
NETWORK
TITLE =EV766 = Avanti Bloccaggio Pallet Laterale Pos di Carico 1 Acc.3

      O     DB110.DBX   32.0;
      O     DB110.DBX   34.5;
      O     DB110.DBX   40.1;
      S     "EV766";
      R     "EV767";
NETWORK
TITLE =EV767 = Indietr Bloccaggio Pallet Laterale Pos di Carico 1 Acc.3

      O     DB110.DBX   32.1;
      O     DB110.DBX   34.6;
      O     DB110.DBX   38.6;
      S     "EV767";
      R     "EV766";
NETWORK
TITLE =EV770 = Salita Fermo Pallet Frontale Pos di Carico 2 Acc.3

      O     DB110.DBX   32.5;
      O     DB110.DBX   35.2;
      O     DB110.DBX   39.1;
      S     "EV770";
      R     "EV771";
NETWORK
TITLE =EV771 = Discesa Fermo Pallet Frontale Pos di Carico 2 Acc.3

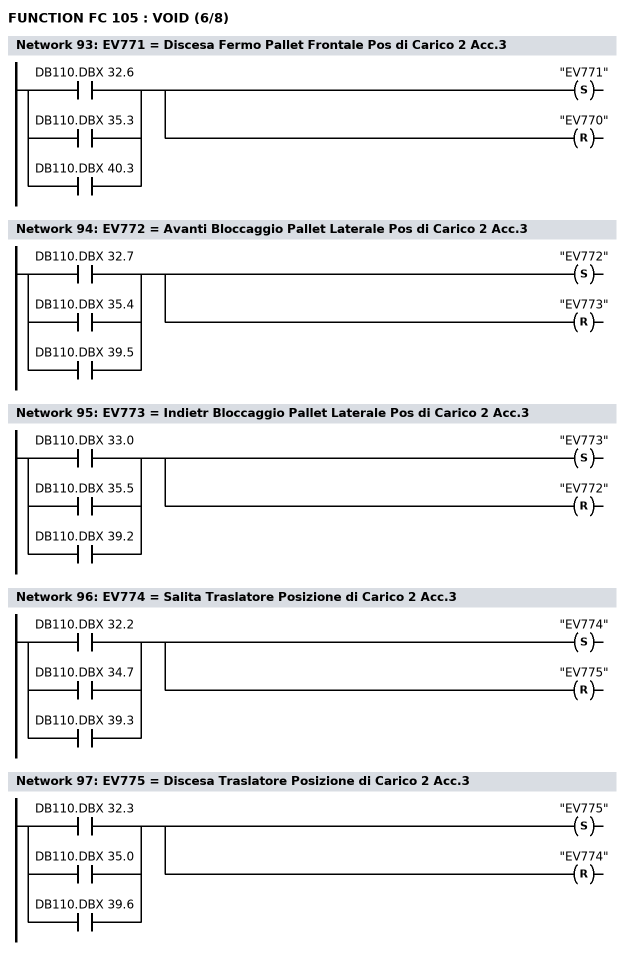
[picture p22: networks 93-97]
      O     DB110.DBX   32.6;
      O     DB110.DBX   35.3;
      O     DB110.DBX   40.3;
      S     "EV771";
      R     "EV770";
NETWORK
TITLE =EV772 = Avanti Bloccaggio Pallet Laterale Pos di Carico 2 Acc.3

      O     DB110.DBX   32.7;
      O     DB110.DBX   35.4;
      O     DB110.DBX   39.5;
      S     "EV772";
      R     "EV773";
NETWORK
TITLE =EV773 = Indietr Bloccaggio Pallet Laterale Pos di Carico 2 Acc.3

      O     DB110.DBX   33.0;
      O     DB110.DBX   35.5;
      O     DB110.DBX   39.2;
      S     "EV773";
      R     "EV772";
NETWORK
TITLE =EV774 = Salita Traslatore Posizione di Carico 2 Acc.3

      O     DB110.DBX   32.2;
      O     DB110.DBX   34.7;
      O     DB110.DBX   39.3;
      S     "EV774";
      R     "EV775";
NETWORK
TITLE =EV775 = Discesa Traslatore Posizione di Carico 2 Acc.3

      O     DB110.DBX   32.3;
      O     DB110.DBX   35.0;
      O     DB110.DBX   39.6;
      S     "EV775";
      R     "EV774";
NETWORK
TITLE =Jog + Attivo Acc.3

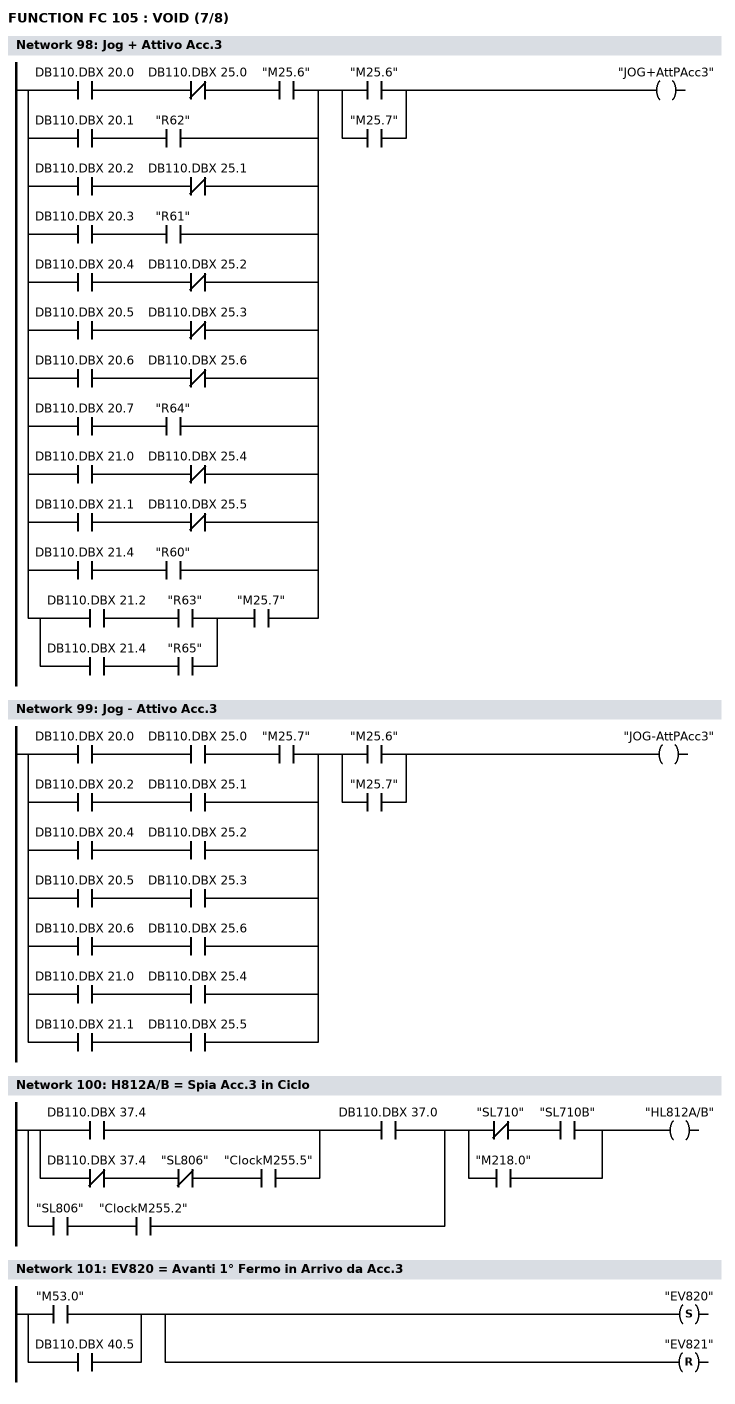
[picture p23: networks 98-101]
      U(    ;
      U     DB110.DBX   20.0;
      UN    DB110.DBX   25.0;
      U     "M25.6";
      O     ;
      U     DB110.DBX   20.1;
      U     "R62";
      O     ;
      U     DB110.DBX   20.2;
      UN    DB110.DBX   25.1;
      O     ;
      U     DB110.DBX   20.3;
      U     "R61";
      O     ;
      U     DB110.DBX   20.4;
      UN    DB110.DBX   25.2;
      O     ;
      U     DB110.DBX   20.5;
      UN    DB110.DBX   25.3;
      O     ;
      U     DB110.DBX   20.6;
      UN    DB110.DBX   25.6;
      O     ;
      U     DB110.DBX   20.7;
      U     "R64";
      O     ;
      U     DB110.DBX   21.0;
      UN    DB110.DBX   25.4;
      O     ;
      U     DB110.DBX   21.1;
      UN    DB110.DBX   25.5;
      O     ;
      U     DB110.DBX   21.4;
      U     "R60";
      O     ;
      U(    ;
      U     DB110.DBX   21.2;
      U     "R63";
      O     ;
      U     DB110.DBX   21.4;
      U     "R65";
      )     ;
      U     "M25.7";
      )     ;
      U(    ;
      O     "M25.6";
      O     "M25.7";
      )     ;
      =     "JOG+AttPAcc3";
NETWORK
TITLE =Jog - Attivo Acc.3

      U(    ;
      U     DB110.DBX   20.0;
      U     DB110.DBX   25.0;
      U     "M25.7";
      O     ;
      U     DB110.DBX   20.2;
      U     DB110.DBX   25.1;
      O     ;
      U     DB110.DBX   20.4;
      U     DB110.DBX   25.2;
      O     ;
      U     DB110.DBX   20.5;
      U     DB110.DBX   25.3;
      O     ;
      U     DB110.DBX   20.6;
      U     DB110.DBX   25.6;
      O     ;
      U     DB110.DBX   21.0;
      U     DB110.DBX   25.4;
      O     ;
      U     DB110.DBX   21.1;
      U     DB110.DBX   25.5;
      )     ;
      U(    ;
      O     "M25.6";
      O     "M25.7";
      )     ;
      =     "JOG-AttPAcc3";
NETWORK
TITLE =H812A/B = Spia Acc.3 in Ciclo

      U(    ;
      U(    ;
      O     DB110.DBX   37.4;
      O     ;
      UN    DB110.DBX   37.4;
      UN    "SL806";
      U     "ClockM255.5";
      )     ;
      U     DB110.DBX   37.0;
      O     ;
      U     "SL806";
      U     "ClockM255.2";
      )     ;
      U(    ;
      UN    "SL710";
      U     "SL710B";
      O     "M218.0";
      )     ;
      =     "HL812A/B";
NETWORK
TITLE =EV820 = Avanti 1° Fermo in Arrivo da Acc.3

      O     "M53.0";
      O     DB110.DBX   40.5;
      S     "EV820";
      R     "EV821";
NETWORK
TITLE =EV821 = Indietro 1° Fermo in Arrivo da Acc.3

      O     "M53.1";
      O     DB110.DBX   40.7;
      S     "EV821";
      R     "EV820";
NETWORK
TITLE =EV822 = Avanti 2° Fermo in Arrivo da Acc.3

      O     "M53.2";
      O     DB110.DBX   40.4;
      S     "EV822";
      R     "EV823";
NETWORK
TITLE =EV823 = Indietro 2° Fermo in Arrivo da Acc.3

      O     "M53.3";
      O     DB110.DBX   40.6;
      S     "EV823";
      R     "EV822";
NETWORK
TITLE =Caricamento Output

      U(    ;
      U(    ;
      L     AW     8;
      T     DB100.DBW    0;
      SET   ;
      SAVE  ;
      CLR   ;
      U     BIE;
      )     ;
      SPBNB _001;
      L     AW    12;
      T     DB100.DBW    2;
      SET   ;
      SAVE  ;
      CLR   ;
_001: U     BIE;
      )     ;
      SPBNB _002;
      L     AW    14;
      T     DB100.DBW    4;
_002: NOP   0;
NETWORK
TITLE =Caricamento Output

      U(    ;
      U(    ;
      L     AW    20;
      T     DB100.DBW    6;
      SET   ;
      SAVE  ;
      CLR   ;
      U     BIE;
      )     ;
      SPBNB _003;
      L     AW    24;
      T     DB100.DBW    8;
      SET   ;
      SAVE  ;
      CLR   ;
_003: U     BIE;
      )     ;
      SPBNB _004;
      L     AW    26;
      T     DB100.DBW   10;
_004: NOP   0;
NETWORK
TITLE =Caricamento Output

      U(    ;
      U(    ;
      L     AW    32;
      T     DB100.DBW   12;
      SET   ;
      SAVE  ;
      CLR   ;
      U     BIE;
      )     ;
      SPBNB _005;
      L     AW    34;
      T     DB100.DBW   14;
      SET   ;
      SAVE  ;
      CLR   ;
_005: U     BIE;
      )     ;
      SPBNB _006;
      L     AW    44;
      T     DB100.DBW   16;
_006: NOP   0;
NETWORK
TITLE =Caricamento Output

      U(    ;
      U(    ;
      L     AW    48;
      T     DB100.DBW   18;
      SET   ;
      SAVE  ;
      CLR   ;
      U     BIE;
      )     ;
      SPBNB _007;
      L     AW    52;
      T     DB100.DBW   20;
      SET   ;
      SAVE  ;
      CLR   ;
_007: U     BIE;
      )     ;
      SPBNB _008;
      L     AW    54;
      T     DB100.DBW   22;
_008: NOP   0;
NETWORK
TITLE =Caricamento Output

      U(    ;
      L     AW    60;
      T     DB100.DBW   24;
      SET   ;
      SAVE  ;
      CLR   ;
      U     BIE;
      )     ;
      SPBNB _009;
      L     AW    64;
      T     DB100.DBW   26;
_009: NOP   0;
NETWORK
TITLE =Caricamento Output

      U(    ;
      L     AW    78;
      T     DB100.DBW   28;
      SET   ;
      SAVE  ;
      CLR   ;
      U     BIE;
      )     ;
      SPBNB _00a;
      L     AW    82;
      T     DB100.DBW   30;
_00a: NOP   0;
END_FUNCTION

